VERSION 5.7 ;
BUSBITCHARS "[]" ;
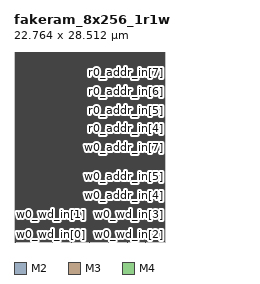
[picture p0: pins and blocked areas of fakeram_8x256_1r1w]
MACRO fakeram_8x256_1r1w
  FOREIGN fakeram_8x256_1r1w 0 0 ;
  SYMMETRY X Y R90 ;
  SIZE 22.764 BY 28.512 ;
  CLASS BLOCK ;
  PIN w0_wd_in[0]
    DIRECTION INPUT ;
    USE SIGNAL ;
    SHAPE ABUTMENT ;
    PORT
      LAYER M2 ;
      RECT 0.000 0.138 0.036 0.150 ;
    END
  END w0_wd_in[0]
  PIN w0_wd_in[1]
    DIRECTION INPUT ;
    USE SIGNAL ;
    SHAPE ABUTMENT ;
    PORT
      LAYER M2 ;
      RECT 0.000 2.946 0.036 2.958 ;
    END
  END w0_wd_in[1]
  PIN w0_wd_in[2]
    DIRECTION INPUT ;
    USE SIGNAL ;
    SHAPE ABUTMENT ;
    PORT
      LAYER M2 ;
      RECT 22.728 0.138 22.764 0.150 ;
    END
  END w0_wd_in[2]
  PIN w0_wd_in[3]
    DIRECTION INPUT ;
    USE SIGNAL ;
    SHAPE ABUTMENT ;
    PORT
      LAYER M2 ;
      RECT 22.728 2.946 22.764 2.958 ;
    END
  END w0_wd_in[3]
  PIN w0_wd_in[4]
    DIRECTION INPUT ;
    USE SIGNAL ;
    SHAPE ABUTMENT ;
    PORT
      LAYER M3 ;
      RECT 0.161 0.000 0.175 0.042 ;
    END
  END w0_wd_in[4]
  PIN w0_wd_in[5]
    DIRECTION INPUT ;
    USE SIGNAL ;
    SHAPE ABUTMENT ;
    PORT
      LAYER M3 ;
      RECT 2.961 0.000 2.975 0.042 ;
    END
  END w0_wd_in[5]
  PIN w0_wd_in[6]
    DIRECTION INPUT ;
    USE SIGNAL ;
    SHAPE ABUTMENT ;
    PORT
      LAYER M3 ;
      RECT 5.761 0.000 5.775 0.042 ;
    END
  END w0_wd_in[6]
  PIN w0_wd_in[7]
    DIRECTION INPUT ;
    USE SIGNAL ;
    SHAPE ABUTMENT ;
    PORT
      LAYER M3 ;
      RECT 8.561 0.000 8.575 0.042 ;
    END
  END w0_wd_in[7]
  PIN r0_rd_out[0]
    DIRECTION OUTPUT ;
    USE SIGNAL ;
    SHAPE ABUTMENT ;
    PORT
      LAYER M3 ;
      RECT 11.361 0.000 11.375 0.042 ;
    END
  END r0_rd_out[0]
  PIN r0_rd_out[1]
    DIRECTION OUTPUT ;
    USE SIGNAL ;
    SHAPE ABUTMENT ;
    PORT
      LAYER M3 ;
      RECT 14.161 0.000 14.175 0.042 ;
    END
  END r0_rd_out[1]
  PIN r0_rd_out[2]
    DIRECTION OUTPUT ;
    USE SIGNAL ;
    SHAPE ABUTMENT ;
    PORT
      LAYER M3 ;
      RECT 16.961 0.000 16.975 0.042 ;
    END
  END r0_rd_out[2]
  PIN r0_rd_out[3]
    DIRECTION OUTPUT ;
    USE SIGNAL ;
    SHAPE ABUTMENT ;
    PORT
      LAYER M3 ;
      RECT 19.761 0.000 19.775 0.042 ;
    END
  END r0_rd_out[3]
  PIN r0_rd_out[4]
    DIRECTION OUTPUT ;
    USE SIGNAL ;
    SHAPE ABUTMENT ;
    PORT
      LAYER M3 ;
      RECT 0.161 28.470 0.175 28.512 ;
    END
  END r0_rd_out[4]
  PIN r0_rd_out[5]
    DIRECTION OUTPUT ;
    USE SIGNAL ;
    SHAPE ABUTMENT ;
    PORT
      LAYER M3 ;
      RECT 2.625 28.470 2.639 28.512 ;
    END
  END r0_rd_out[5]
  PIN r0_rd_out[6]
    DIRECTION OUTPUT ;
    USE SIGNAL ;
    SHAPE ABUTMENT ;
    PORT
      LAYER M3 ;
      RECT 5.089 28.470 5.103 28.512 ;
    END
  END r0_rd_out[6]
  PIN r0_rd_out[7]
    DIRECTION OUTPUT ;
    USE SIGNAL ;
    SHAPE ABUTMENT ;
    PORT
      LAYER M3 ;
      RECT 7.553 28.470 7.567 28.512 ;
    END
  END r0_rd_out[7]
  PIN w0_addr_in[0]
    DIRECTION INPUT ;
    USE SIGNAL ;
    SHAPE ABUTMENT ;
    PORT
      LAYER M2 ;
      RECT 0.000 5.754 0.036 5.766 ;
    END
  END w0_addr_in[0]
  PIN w0_addr_in[1]
    DIRECTION INPUT ;
    USE SIGNAL ;
    SHAPE ABUTMENT ;
    PORT
      LAYER M2 ;
      RECT 0.000 8.562 0.036 8.574 ;
    END
  END w0_addr_in[1]
  PIN w0_addr_in[2]
    DIRECTION INPUT ;
    USE SIGNAL ;
    SHAPE ABUTMENT ;
    PORT
      LAYER M2 ;
      RECT 0.000 11.370 0.036 11.382 ;
    END
  END w0_addr_in[2]
  PIN w0_addr_in[3]
    DIRECTION INPUT ;
    USE SIGNAL ;
    SHAPE ABUTMENT ;
    PORT
      LAYER M2 ;
      RECT 0.000 14.178 0.036 14.190 ;
    END
  END w0_addr_in[3]
  PIN w0_addr_in[4]
    DIRECTION INPUT ;
    USE SIGNAL ;
    SHAPE ABUTMENT ;
    PORT
      LAYER M2 ;
      RECT 22.728 5.754 22.764 5.766 ;
    END
  END w0_addr_in[4]
  PIN w0_addr_in[5]
    DIRECTION INPUT ;
    USE SIGNAL ;
    SHAPE ABUTMENT ;
    PORT
      LAYER M2 ;
      RECT 22.728 8.562 22.764 8.574 ;
    END
  END w0_addr_in[5]
  PIN w0_addr_in[6]
    DIRECTION INPUT ;
    USE SIGNAL ;
    SHAPE ABUTMENT ;
    PORT
      LAYER M2 ;
      RECT 22.728 11.370 22.764 11.382 ;
    END
  END w0_addr_in[6]
  PIN w0_addr_in[7]
    DIRECTION INPUT ;
    USE SIGNAL ;
    SHAPE ABUTMENT ;
    PORT
      LAYER M2 ;
      RECT 22.728 14.178 22.764 14.190 ;
    END
  END w0_addr_in[7]
  PIN r0_addr_in[0]
    DIRECTION INPUT ;
    USE SIGNAL ;
    SHAPE ABUTMENT ;
    PORT
      LAYER M2 ;
      RECT 0.000 16.986 0.036 16.998 ;
    END
  END r0_addr_in[0]
  PIN r0_addr_in[1]
    DIRECTION INPUT ;
    USE SIGNAL ;
    SHAPE ABUTMENT ;
    PORT
      LAYER M2 ;
      RECT 0.000 19.794 0.036 19.806 ;
    END
  END r0_addr_in[1]
  PIN r0_addr_in[2]
    DIRECTION INPUT ;
    USE SIGNAL ;
    SHAPE ABUTMENT ;
    PORT
      LAYER M2 ;
      RECT 0.000 22.602 0.036 22.614 ;
    END
  END r0_addr_in[2]
  PIN r0_addr_in[3]
    DIRECTION INPUT ;
    USE SIGNAL ;
    SHAPE ABUTMENT ;
    PORT
      LAYER M2 ;
      RECT 0.000 25.410 0.036 25.422 ;
    END
  END r0_addr_in[3]
  PIN r0_addr_in[4]
    DIRECTION INPUT ;
    USE SIGNAL ;
    SHAPE ABUTMENT ;
    PORT
      LAYER M2 ;
      RECT 22.728 16.986 22.764 16.998 ;
    END
  END r0_addr_in[4]
  PIN r0_addr_in[5]
    DIRECTION INPUT ;
    USE SIGNAL ;
    SHAPE ABUTMENT ;
    PORT
      LAYER M2 ;
      RECT 22.728 19.794 22.764 19.806 ;
    END
  END r0_addr_in[5]
  PIN r0_addr_in[6]
    DIRECTION INPUT ;
    USE SIGNAL ;
    SHAPE ABUTMENT ;
    PORT
      LAYER M2 ;
      RECT 22.728 22.602 22.764 22.614 ;
    END
  END r0_addr_in[6]
  PIN r0_addr_in[7]
    DIRECTION INPUT ;
    USE SIGNAL ;
    SHAPE ABUTMENT ;
    PORT
      LAYER M2 ;
      RECT 22.728 25.410 22.764 25.422 ;
    END
  END r0_addr_in[7]
  PIN w0_we_in
    DIRECTION INPUT ;
    USE SIGNAL ;
    SHAPE ABUTMENT ;
    PORT
      LAYER M3 ;
      RECT 10.017 28.470 10.031 28.512 ;
    END
  END w0_we_in
  PIN w0_ce_in
    DIRECTION INPUT ;
    USE SIGNAL ;
    SHAPE ABUTMENT ;
    PORT
      LAYER M3 ;
      RECT 12.481 28.470 12.495 28.512 ;
    END
  END w0_ce_in
  PIN w0_clk
    DIRECTION INPUT ;
    USE SIGNAL ;
    SHAPE ABUTMENT ;
    PORT
      LAYER M3 ;
      RECT 14.945 28.470 14.959 28.512 ;
    END
  END w0_clk
  PIN r0_ce_in
    DIRECTION INPUT ;
    USE SIGNAL ;
    SHAPE ABUTMENT ;
    PORT
      LAYER M3 ;
      RECT 17.409 28.470 17.423 28.512 ;
    END
  END r0_ce_in
  PIN r0_clk
    DIRECTION INPUT ;
    USE SIGNAL ;
    SHAPE ABUTMENT ;
    PORT
      LAYER M3 ;
      RECT 19.873 28.470 19.887 28.512 ;
    END
  END r0_clk
  PIN VSS
    DIRECTION INOUT ;
    USE GROUND ;
    PORT
      LAYER M4 ;
      RECT 0.168 0.120 22.596 0.168 ;
      RECT 0.168 0.504 22.596 0.552 ;
      RECT 0.168 0.888 22.596 0.936 ;
      RECT 0.168 1.272 22.596 1.320 ;
      RECT 0.168 1.656 22.596 1.704 ;
      RECT 0.168 2.040 22.596 2.088 ;
      RECT 0.168 2.424 22.596 2.472 ;
      RECT 0.168 2.808 22.596 2.856 ;
      RECT 0.168 3.192 22.596 3.240 ;
      RECT 0.168 3.576 22.596 3.624 ;
      RECT 0.168 3.960 22.596 4.008 ;
      RECT 0.168 4.344 22.596 4.392 ;
      RECT 0.168 4.728 22.596 4.776 ;
      RECT 0.168 5.112 22.596 5.160 ;
      RECT 0.168 5.496 22.596 5.544 ;
      RECT 0.168 5.880 22.596 5.928 ;
      RECT 0.168 6.264 22.596 6.312 ;
      RECT 0.168 6.648 22.596 6.696 ;
      RECT 0.168 7.032 22.596 7.080 ;
      RECT 0.168 7.416 22.596 7.464 ;
      RECT 0.168 7.800 22.596 7.848 ;
      RECT 0.168 8.184 22.596 8.232 ;
      RECT 0.168 8.568 22.596 8.616 ;
      RECT 0.168 8.952 22.596 9.000 ;
      RECT 0.168 9.336 22.596 9.384 ;
      RECT 0.168 9.720 22.596 9.768 ;
      RECT 0.168 10.104 22.596 10.152 ;
      RECT 0.168 10.488 22.596 10.536 ;
      RECT 0.168 10.872 22.596 10.920 ;
      RECT 0.168 11.256 22.596 11.304 ;
      RECT 0.168 11.640 22.596 11.688 ;
      RECT 0.168 12.024 22.596 12.072 ;
      RECT 0.168 12.408 22.596 12.456 ;
      RECT 0.168 12.792 22.596 12.840 ;
      RECT 0.168 13.176 22.596 13.224 ;
      RECT 0.168 13.560 22.596 13.608 ;
      RECT 0.168 13.944 22.596 13.992 ;
      RECT 0.168 14.328 22.596 14.376 ;
      RECT 0.168 14.712 22.596 14.760 ;
      RECT 0.168 15.096 22.596 15.144 ;
      RECT 0.168 15.480 22.596 15.528 ;
      RECT 0.168 15.864 22.596 15.912 ;
      RECT 0.168 16.248 22.596 16.296 ;
      RECT 0.168 16.632 22.596 16.680 ;
      RECT 0.168 17.016 22.596 17.064 ;
      RECT 0.168 17.400 22.596 17.448 ;
      RECT 0.168 17.784 22.596 17.832 ;
      RECT 0.168 18.168 22.596 18.216 ;
      RECT 0.168 18.552 22.596 18.600 ;
      RECT 0.168 18.936 22.596 18.984 ;
      RECT 0.168 19.320 22.596 19.368 ;
      RECT 0.168 19.704 22.596 19.752 ;
      RECT 0.168 20.088 22.596 20.136 ;
      RECT 0.168 20.472 22.596 20.520 ;
      RECT 0.168 20.856 22.596 20.904 ;
      RECT 0.168 21.240 22.596 21.288 ;
      RECT 0.168 21.624 22.596 21.672 ;
      RECT 0.168 22.008 22.596 22.056 ;
      RECT 0.168 22.392 22.596 22.440 ;
      RECT 0.168 22.776 22.596 22.824 ;
      RECT 0.168 23.160 22.596 23.208 ;
      RECT 0.168 23.544 22.596 23.592 ;
      RECT 0.168 23.928 22.596 23.976 ;
      RECT 0.168 24.312 22.596 24.360 ;
      RECT 0.168 24.696 22.596 24.744 ;
      RECT 0.168 25.080 22.596 25.128 ;
      RECT 0.168 25.464 22.596 25.512 ;
      RECT 0.168 25.848 22.596 25.896 ;
      RECT 0.168 26.232 22.596 26.280 ;
      RECT 0.168 26.616 22.596 26.664 ;
      RECT 0.168 27.000 22.596 27.048 ;
      RECT 0.168 27.384 22.596 27.432 ;
      RECT 0.168 27.768 22.596 27.816 ;
      RECT 0.168 28.152 22.596 28.200 ;
    END
  END VSS
  PIN VDD
    DIRECTION INOUT ;
    USE POWER ;
    PORT
      LAYER M4 ;
      RECT 0.168 0.312 22.596 0.360 ;
      RECT 0.168 0.696 22.596 0.744 ;
      RECT 0.168 1.080 22.596 1.128 ;
      RECT 0.168 1.464 22.596 1.512 ;
      RECT 0.168 1.848 22.596 1.896 ;
      RECT 0.168 2.232 22.596 2.280 ;
      RECT 0.168 2.616 22.596 2.664 ;
      RECT 0.168 3.000 22.596 3.048 ;
      RECT 0.168 3.384 22.596 3.432 ;
      RECT 0.168 3.768 22.596 3.816 ;
      RECT 0.168 4.152 22.596 4.200 ;
      RECT 0.168 4.536 22.596 4.584 ;
      RECT 0.168 4.920 22.596 4.968 ;
      RECT 0.168 5.304 22.596 5.352 ;
      RECT 0.168 5.688 22.596 5.736 ;
      RECT 0.168 6.072 22.596 6.120 ;
      RECT 0.168 6.456 22.596 6.504 ;
      RECT 0.168 6.840 22.596 6.888 ;
      RECT 0.168 7.224 22.596 7.272 ;
      RECT 0.168 7.608 22.596 7.656 ;
      RECT 0.168 7.992 22.596 8.040 ;
      RECT 0.168 8.376 22.596 8.424 ;
      RECT 0.168 8.760 22.596 8.808 ;
      RECT 0.168 9.144 22.596 9.192 ;
      RECT 0.168 9.528 22.596 9.576 ;
      RECT 0.168 9.912 22.596 9.960 ;
      RECT 0.168 10.296 22.596 10.344 ;
      RECT 0.168 10.680 22.596 10.728 ;
      RECT 0.168 11.064 22.596 11.112 ;
      RECT 0.168 11.448 22.596 11.496 ;
      RECT 0.168 11.832 22.596 11.880 ;
      RECT 0.168 12.216 22.596 12.264 ;
      RECT 0.168 12.600 22.596 12.648 ;
      RECT 0.168 12.984 22.596 13.032 ;
      RECT 0.168 13.368 22.596 13.416 ;
      RECT 0.168 13.752 22.596 13.800 ;
      RECT 0.168 14.136 22.596 14.184 ;
      RECT 0.168 14.520 22.596 14.568 ;
      RECT 0.168 14.904 22.596 14.952 ;
      RECT 0.168 15.288 22.596 15.336 ;
      RECT 0.168 15.672 22.596 15.720 ;
      RECT 0.168 16.056 22.596 16.104 ;
      RECT 0.168 16.440 22.596 16.488 ;
      RECT 0.168 16.824 22.596 16.872 ;
      RECT 0.168 17.208 22.596 17.256 ;
      RECT 0.168 17.592 22.596 17.640 ;
      RECT 0.168 17.976 22.596 18.024 ;
      RECT 0.168 18.360 22.596 18.408 ;
      RECT 0.168 18.744 22.596 18.792 ;
      RECT 0.168 19.128 22.596 19.176 ;
      RECT 0.168 19.512 22.596 19.560 ;
      RECT 0.168 19.896 22.596 19.944 ;
      RECT 0.168 20.280 22.596 20.328 ;
      RECT 0.168 20.664 22.596 20.712 ;
      RECT 0.168 21.048 22.596 21.096 ;
      RECT 0.168 21.432 22.596 21.480 ;
      RECT 0.168 21.816 22.596 21.864 ;
      RECT 0.168 22.200 22.596 22.248 ;
      RECT 0.168 22.584 22.596 22.632 ;
      RECT 0.168 22.968 22.596 23.016 ;
      RECT 0.168 23.352 22.596 23.400 ;
      RECT 0.168 23.736 22.596 23.784 ;
      RECT 0.168 24.120 22.596 24.168 ;
      RECT 0.168 24.504 22.596 24.552 ;
      RECT 0.168 24.888 22.596 24.936 ;
      RECT 0.168 25.272 22.596 25.320 ;
      RECT 0.168 25.656 22.596 25.704 ;
      RECT 0.168 26.040 22.596 26.088 ;
      RECT 0.168 26.424 22.596 26.472 ;
      RECT 0.168 26.808 22.596 26.856 ;
      RECT 0.168 27.192 22.596 27.240 ;
      RECT 0.168 27.576 22.596 27.624 ;
      RECT 0.168 27.960 22.596 28.008 ;
      RECT 0.168 28.344 22.596 28.392 ;
    END
  END VDD
  OBS
    LAYER M1 ;
    RECT 0 0 22.764 28.512 ;
    LAYER M2 ;
    RECT 0 0 22.764 28.512 ;
    LAYER M3 ;
    RECT 0 0 22.764 28.512 ;
    LAYER M4 ;
    RECT 0 0 22.764 28.512 ;
  END
END fakeram_8x256_1r1w

END LIBRARY
